VERSION 5.7 ;
  NOWIREEXTENSIONATPIN ON ;
  DIVIDERCHAR "/" ;
  BUSBITCHARS "[]" ;
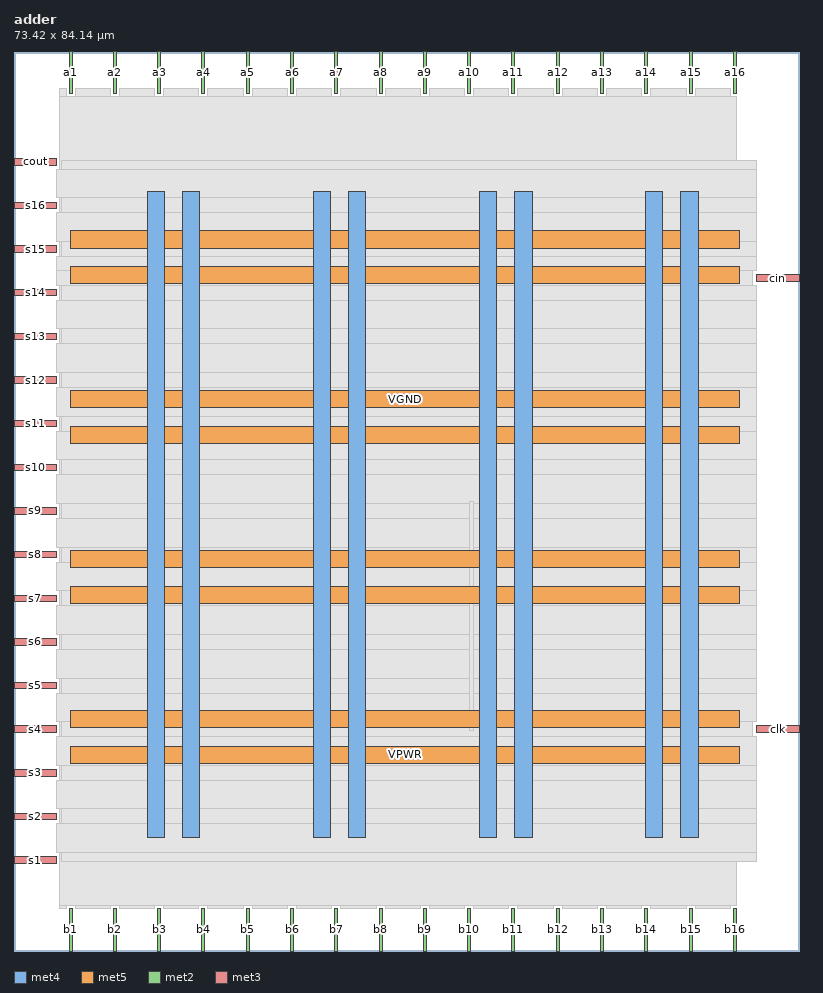
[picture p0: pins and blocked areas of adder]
MACRO adder
  CLASS BLOCK ;
  FOREIGN adder ;
  ORIGIN 0.000 0.000 ;
  SIZE 73.420 BY 84.140 ;
  PIN VGND
    DIRECTION INOUT ;
    USE GROUND ;
    PORT
      LAYER met4 ;
        RECT 15.780 10.640 17.380 70.960 ;
    END
    PORT
      LAYER met4 ;
        RECT 31.305 10.640 32.905 70.960 ;
    END
    PORT
      LAYER met4 ;
        RECT 46.830 10.640 48.430 70.960 ;
    END
    PORT
      LAYER met4 ;
        RECT 62.355 10.640 63.955 70.960 ;
    END
    PORT
      LAYER met5 ;
        RECT 5.280 20.855 67.860 22.455 ;
    END
    PORT
      LAYER met5 ;
        RECT 5.280 35.810 67.860 37.410 ;
    END
    PORT
      LAYER met5 ;
        RECT 5.280 50.765 67.860 52.365 ;
    END
    PORT
      LAYER met5 ;
        RECT 5.280 65.720 67.860 67.320 ;
    END
  END VGND
  PIN VPWR
    DIRECTION INOUT ;
    USE POWER ;
    PORT
      LAYER met4 ;
        RECT 12.480 10.640 14.080 70.960 ;
    END
    PORT
      LAYER met4 ;
        RECT 28.005 10.640 29.605 70.960 ;
    END
    PORT
      LAYER met4 ;
        RECT 43.530 10.640 45.130 70.960 ;
    END
    PORT
      LAYER met4 ;
        RECT 59.055 10.640 60.655 70.960 ;
    END
    PORT
      LAYER met5 ;
        RECT 5.280 17.555 67.860 19.155 ;
    END
    PORT
      LAYER met5 ;
        RECT 5.280 32.510 67.860 34.110 ;
    END
    PORT
      LAYER met5 ;
        RECT 5.280 47.465 67.860 49.065 ;
    END
    PORT
      LAYER met5 ;
        RECT 5.280 62.420 67.860 64.020 ;
    END
  END VPWR
  PIN a1
    DIRECTION INPUT ;
    USE SIGNAL ;
    ANTENNAGATEAREA 0.196500 ;
    PORT
      LAYER met2 ;
        RECT 5.150 80.140 5.430 84.140 ;
    END
  END a1
  PIN a10
    DIRECTION INPUT ;
    USE SIGNAL ;
    ANTENNAGATEAREA 0.196500 ;
    PORT
      LAYER met2 ;
        RECT 42.410 80.140 42.690 84.140 ;
    END
  END a10
  PIN a11
    DIRECTION INPUT ;
    USE SIGNAL ;
    ANTENNAGATEAREA 0.196500 ;
    PORT
      LAYER met2 ;
        RECT 46.550 80.140 46.830 84.140 ;
    END
  END a11
  PIN a12
    DIRECTION INPUT ;
    USE SIGNAL ;
    ANTENNAGATEAREA 0.196500 ;
    PORT
      LAYER met2 ;
        RECT 50.690 80.140 50.970 84.140 ;
    END
  END a12
  PIN a13
    DIRECTION INPUT ;
    USE SIGNAL ;
    ANTENNAGATEAREA 0.196500 ;
    PORT
      LAYER met2 ;
        RECT 54.830 80.140 55.110 84.140 ;
    END
  END a13
  PIN a14
    DIRECTION INPUT ;
    USE SIGNAL ;
    ANTENNAGATEAREA 0.196500 ;
    PORT
      LAYER met2 ;
        RECT 58.970 80.140 59.250 84.140 ;
    END
  END a14
  PIN a15
    DIRECTION INPUT ;
    USE SIGNAL ;
    ANTENNAGATEAREA 0.196500 ;
    PORT
      LAYER met2 ;
        RECT 63.110 80.140 63.390 84.140 ;
    END
  END a15
  PIN a16
    DIRECTION INPUT ;
    USE SIGNAL ;
    ANTENNAGATEAREA 0.196500 ;
    PORT
      LAYER met2 ;
        RECT 67.250 80.140 67.530 84.140 ;
    END
  END a16
  PIN a2
    DIRECTION INPUT ;
    USE SIGNAL ;
    ANTENNAGATEAREA 0.196500 ;
    PORT
      LAYER met2 ;
        RECT 9.290 80.140 9.570 84.140 ;
    END
  END a2
  PIN a3
    DIRECTION INPUT ;
    USE SIGNAL ;
    ANTENNAGATEAREA 0.196500 ;
    PORT
      LAYER met2 ;
        RECT 13.430 80.140 13.710 84.140 ;
    END
  END a3
  PIN a4
    DIRECTION INPUT ;
    USE SIGNAL ;
    ANTENNAGATEAREA 0.196500 ;
    PORT
      LAYER met2 ;
        RECT 17.570 80.140 17.850 84.140 ;
    END
  END a4
  PIN a5
    DIRECTION INPUT ;
    USE SIGNAL ;
    ANTENNAGATEAREA 0.196500 ;
    PORT
      LAYER met2 ;
        RECT 21.710 80.140 21.990 84.140 ;
    END
  END a5
  PIN a6
    DIRECTION INPUT ;
    USE SIGNAL ;
    ANTENNAGATEAREA 0.196500 ;
    PORT
      LAYER met2 ;
        RECT 25.850 80.140 26.130 84.140 ;
    END
  END a6
  PIN a7
    DIRECTION INPUT ;
    USE SIGNAL ;
    ANTENNAGATEAREA 0.196500 ;
    PORT
      LAYER met2 ;
        RECT 29.990 80.140 30.270 84.140 ;
    END
  END a7
  PIN a8
    DIRECTION INPUT ;
    USE SIGNAL ;
    ANTENNAGATEAREA 0.196500 ;
    PORT
      LAYER met2 ;
        RECT 34.130 80.140 34.410 84.140 ;
    END
  END a8
  PIN a9
    DIRECTION INPUT ;
    USE SIGNAL ;
    ANTENNAGATEAREA 0.196500 ;
    PORT
      LAYER met2 ;
        RECT 38.270 80.140 38.550 84.140 ;
    END
  END a9
  PIN b1
    DIRECTION INPUT ;
    USE SIGNAL ;
    ANTENNAGATEAREA 0.196500 ;
    PORT
      LAYER met2 ;
        RECT 5.150 0.000 5.430 4.000 ;
    END
  END b1
  PIN b10
    DIRECTION INPUT ;
    USE SIGNAL ;
    ANTENNAGATEAREA 0.196500 ;
    PORT
      LAYER met2 ;
        RECT 42.410 0.000 42.690 4.000 ;
    END
  END b10
  PIN b11
    DIRECTION INPUT ;
    USE SIGNAL ;
    ANTENNAGATEAREA 0.196500 ;
    PORT
      LAYER met2 ;
        RECT 46.550 0.000 46.830 4.000 ;
    END
  END b11
  PIN b12
    DIRECTION INPUT ;
    USE SIGNAL ;
    ANTENNAGATEAREA 0.196500 ;
    PORT
      LAYER met2 ;
        RECT 50.690 0.000 50.970 4.000 ;
    END
  END b12
  PIN b13
    DIRECTION INPUT ;
    USE SIGNAL ;
    ANTENNAGATEAREA 0.196500 ;
    PORT
      LAYER met2 ;
        RECT 54.830 0.000 55.110 4.000 ;
    END
  END b13
  PIN b14
    DIRECTION INPUT ;
    USE SIGNAL ;
    ANTENNAGATEAREA 0.196500 ;
    PORT
      LAYER met2 ;
        RECT 58.970 0.000 59.250 4.000 ;
    END
  END b14
  PIN b15
    DIRECTION INPUT ;
    USE SIGNAL ;
    ANTENNAGATEAREA 0.196500 ;
    PORT
      LAYER met2 ;
        RECT 63.110 0.000 63.390 4.000 ;
    END
  END b15
  PIN b16
    DIRECTION INPUT ;
    USE SIGNAL ;
    ANTENNAGATEAREA 0.196500 ;
    PORT
      LAYER met2 ;
        RECT 67.250 0.000 67.530 4.000 ;
    END
  END b16
  PIN b2
    DIRECTION INPUT ;
    USE SIGNAL ;
    ANTENNAGATEAREA 0.196500 ;
    PORT
      LAYER met2 ;
        RECT 9.290 0.000 9.570 4.000 ;
    END
  END b2
  PIN b3
    DIRECTION INPUT ;
    USE SIGNAL ;
    ANTENNAGATEAREA 0.196500 ;
    PORT
      LAYER met2 ;
        RECT 13.430 0.000 13.710 4.000 ;
    END
  END b3
  PIN b4
    DIRECTION INPUT ;
    USE SIGNAL ;
    ANTENNAGATEAREA 0.196500 ;
    PORT
      LAYER met2 ;
        RECT 17.570 0.000 17.850 4.000 ;
    END
  END b4
  PIN b5
    DIRECTION INPUT ;
    USE SIGNAL ;
    ANTENNAGATEAREA 0.196500 ;
    PORT
      LAYER met2 ;
        RECT 21.710 0.000 21.990 4.000 ;
    END
  END b5
  PIN b6
    DIRECTION INPUT ;
    USE SIGNAL ;
    ANTENNAGATEAREA 0.196500 ;
    PORT
      LAYER met2 ;
        RECT 25.850 0.000 26.130 4.000 ;
    END
  END b6
  PIN b7
    DIRECTION INPUT ;
    USE SIGNAL ;
    ANTENNAGATEAREA 0.196500 ;
    PORT
      LAYER met2 ;
        RECT 29.990 0.000 30.270 4.000 ;
    END
  END b7
  PIN b8
    DIRECTION INPUT ;
    USE SIGNAL ;
    ANTENNAGATEAREA 0.196500 ;
    PORT
      LAYER met2 ;
        RECT 34.130 0.000 34.410 4.000 ;
    END
  END b8
  PIN b9
    DIRECTION INPUT ;
    USE SIGNAL ;
    ANTENNAGATEAREA 0.196500 ;
    PORT
      LAYER met2 ;
        RECT 38.270 0.000 38.550 4.000 ;
    END
  END b9
  PIN cin
    DIRECTION INPUT ;
    USE SIGNAL ;
    ANTENNAGATEAREA 0.196500 ;
    PORT
      LAYER met3 ;
        RECT 69.420 62.600 73.420 63.200 ;
    END
  END cin
  PIN clk
    DIRECTION INPUT ;
    USE SIGNAL ;
    ANTENNAGATEAREA 0.852000 ;
    PORT
      LAYER met3 ;
        RECT 69.420 20.440 73.420 21.040 ;
    END
  END clk
  PIN cout
    DIRECTION OUTPUT ;
    USE SIGNAL ;
    ANTENNADIFFAREA 0.340600 ;
    PORT
      LAYER met3 ;
        RECT 0.000 73.480 4.000 74.080 ;
    END
  END cout
  PIN s1
    DIRECTION OUTPUT ;
    USE SIGNAL ;
    ANTENNADIFFAREA 0.340600 ;
    PORT
      LAYER met3 ;
        RECT 0.000 8.200 4.000 8.800 ;
    END
  END s1
  PIN s10
    DIRECTION OUTPUT ;
    USE SIGNAL ;
    ANTENNADIFFAREA 0.340600 ;
    PORT
      LAYER met3 ;
        RECT 0.000 44.920 4.000 45.520 ;
    END
  END s10
  PIN s11
    DIRECTION OUTPUT ;
    USE SIGNAL ;
    ANTENNADIFFAREA 0.340600 ;
    PORT
      LAYER met3 ;
        RECT 0.000 49.000 4.000 49.600 ;
    END
  END s11
  PIN s12
    DIRECTION OUTPUT ;
    USE SIGNAL ;
    ANTENNADIFFAREA 0.340600 ;
    PORT
      LAYER met3 ;
        RECT 0.000 53.080 4.000 53.680 ;
    END
  END s12
  PIN s13
    DIRECTION OUTPUT ;
    USE SIGNAL ;
    ANTENNADIFFAREA 0.340600 ;
    PORT
      LAYER met3 ;
        RECT 0.000 57.160 4.000 57.760 ;
    END
  END s13
  PIN s14
    DIRECTION OUTPUT ;
    USE SIGNAL ;
    ANTENNADIFFAREA 0.340600 ;
    PORT
      LAYER met3 ;
        RECT 0.000 61.240 4.000 61.840 ;
    END
  END s14
  PIN s15
    DIRECTION OUTPUT ;
    USE SIGNAL ;
    ANTENNADIFFAREA 0.340600 ;
    PORT
      LAYER met3 ;
        RECT 0.000 65.320 4.000 65.920 ;
    END
  END s15
  PIN s16
    DIRECTION OUTPUT ;
    USE SIGNAL ;
    ANTENNADIFFAREA 0.340600 ;
    PORT
      LAYER met3 ;
        RECT 0.000 69.400 4.000 70.000 ;
    END
  END s16
  PIN s2
    DIRECTION OUTPUT ;
    USE SIGNAL ;
    ANTENNADIFFAREA 0.340600 ;
    PORT
      LAYER met3 ;
        RECT 0.000 12.280 4.000 12.880 ;
    END
  END s2
  PIN s3
    DIRECTION OUTPUT ;
    USE SIGNAL ;
    ANTENNADIFFAREA 0.340600 ;
    PORT
      LAYER met3 ;
        RECT 0.000 16.360 4.000 16.960 ;
    END
  END s3
  PIN s4
    DIRECTION OUTPUT ;
    USE SIGNAL ;
    ANTENNADIFFAREA 0.340600 ;
    PORT
      LAYER met3 ;
        RECT 0.000 20.440 4.000 21.040 ;
    END
  END s4
  PIN s5
    DIRECTION OUTPUT ;
    USE SIGNAL ;
    ANTENNADIFFAREA 0.340600 ;
    PORT
      LAYER met3 ;
        RECT 0.000 24.520 4.000 25.120 ;
    END
  END s5
  PIN s6
    DIRECTION OUTPUT ;
    USE SIGNAL ;
    ANTENNADIFFAREA 0.340600 ;
    PORT
      LAYER met3 ;
        RECT 0.000 28.600 4.000 29.200 ;
    END
  END s6
  PIN s7
    DIRECTION OUTPUT ;
    USE SIGNAL ;
    ANTENNADIFFAREA 0.340600 ;
    PORT
      LAYER met3 ;
        RECT 0.000 32.680 4.000 33.280 ;
    END
  END s7
  PIN s8
    DIRECTION OUTPUT ;
    USE SIGNAL ;
    ANTENNADIFFAREA 0.340600 ;
    PORT
      LAYER met3 ;
        RECT 0.000 36.760 4.000 37.360 ;
    END
  END s8
  PIN s9
    DIRECTION OUTPUT ;
    USE SIGNAL ;
    ANTENNADIFFAREA 0.340600 ;
    PORT
      LAYER met3 ;
        RECT 0.000 40.840 4.000 41.440 ;
    END
  END s9
  OBS
      LAYER nwell ;
        RECT 5.330 10.795 67.810 70.805 ;
      LAYER li1 ;
        RECT 5.520 10.795 67.620 70.805 ;
      LAYER met1 ;
        RECT 4.210 10.640 67.920 70.960 ;
      LAYER met2 ;
        RECT 4.230 79.860 4.870 80.650 ;
        RECT 5.710 79.860 9.010 80.650 ;
        RECT 9.850 79.860 13.150 80.650 ;
        RECT 13.990 79.860 17.290 80.650 ;
        RECT 18.130 79.860 21.430 80.650 ;
        RECT 22.270 79.860 25.570 80.650 ;
        RECT 26.410 79.860 29.710 80.650 ;
        RECT 30.550 79.860 33.850 80.650 ;
        RECT 34.690 79.860 37.990 80.650 ;
        RECT 38.830 79.860 42.130 80.650 ;
        RECT 42.970 79.860 46.270 80.650 ;
        RECT 47.110 79.860 50.410 80.650 ;
        RECT 51.250 79.860 54.550 80.650 ;
        RECT 55.390 79.860 58.690 80.650 ;
        RECT 59.530 79.860 62.830 80.650 ;
        RECT 63.670 79.860 66.970 80.650 ;
        RECT 4.230 4.280 67.520 79.860 ;
        RECT 4.230 4.000 4.870 4.280 ;
        RECT 5.710 4.000 9.010 4.280 ;
        RECT 9.850 4.000 13.150 4.280 ;
        RECT 13.990 4.000 17.290 4.280 ;
        RECT 18.130 4.000 21.430 4.280 ;
        RECT 22.270 4.000 25.570 4.280 ;
        RECT 26.410 4.000 29.710 4.280 ;
        RECT 30.550 4.000 33.850 4.280 ;
        RECT 34.690 4.000 37.990 4.280 ;
        RECT 38.830 4.000 42.130 4.280 ;
        RECT 42.970 4.000 46.270 4.280 ;
        RECT 47.110 4.000 50.410 4.280 ;
        RECT 51.250 4.000 54.550 4.280 ;
        RECT 55.390 4.000 58.690 4.280 ;
        RECT 59.530 4.000 62.830 4.280 ;
        RECT 63.670 4.000 66.970 4.280 ;
      LAYER met3 ;
        RECT 4.400 73.080 69.420 73.945 ;
        RECT 3.990 70.400 69.420 73.080 ;
        RECT 4.400 69.000 69.420 70.400 ;
        RECT 3.990 66.320 69.420 69.000 ;
        RECT 4.400 64.920 69.420 66.320 ;
        RECT 3.990 63.600 69.420 64.920 ;
        RECT 3.990 62.240 69.020 63.600 ;
        RECT 4.400 62.200 69.020 62.240 ;
        RECT 4.400 60.840 69.420 62.200 ;
        RECT 3.990 58.160 69.420 60.840 ;
        RECT 4.400 56.760 69.420 58.160 ;
        RECT 3.990 54.080 69.420 56.760 ;
        RECT 4.400 52.680 69.420 54.080 ;
        RECT 3.990 50.000 69.420 52.680 ;
        RECT 4.400 48.600 69.420 50.000 ;
        RECT 3.990 45.920 69.420 48.600 ;
        RECT 4.400 44.520 69.420 45.920 ;
        RECT 3.990 41.840 69.420 44.520 ;
        RECT 4.400 40.440 69.420 41.840 ;
        RECT 3.990 37.760 69.420 40.440 ;
        RECT 4.400 36.360 69.420 37.760 ;
        RECT 3.990 33.680 69.420 36.360 ;
        RECT 4.400 32.280 69.420 33.680 ;
        RECT 3.990 29.600 69.420 32.280 ;
        RECT 4.400 28.200 69.420 29.600 ;
        RECT 3.990 25.520 69.420 28.200 ;
        RECT 4.400 24.120 69.420 25.520 ;
        RECT 3.990 21.440 69.420 24.120 ;
        RECT 4.400 20.040 69.020 21.440 ;
        RECT 3.990 17.360 69.420 20.040 ;
        RECT 4.400 15.960 69.420 17.360 ;
        RECT 3.990 13.280 69.420 15.960 ;
        RECT 4.400 11.880 69.420 13.280 ;
        RECT 3.990 9.200 69.420 11.880 ;
        RECT 4.400 8.335 69.420 9.200 ;
      LAYER met4 ;
        RECT 42.615 20.575 42.945 41.985 ;
  END
END adder
END LIBRARY

